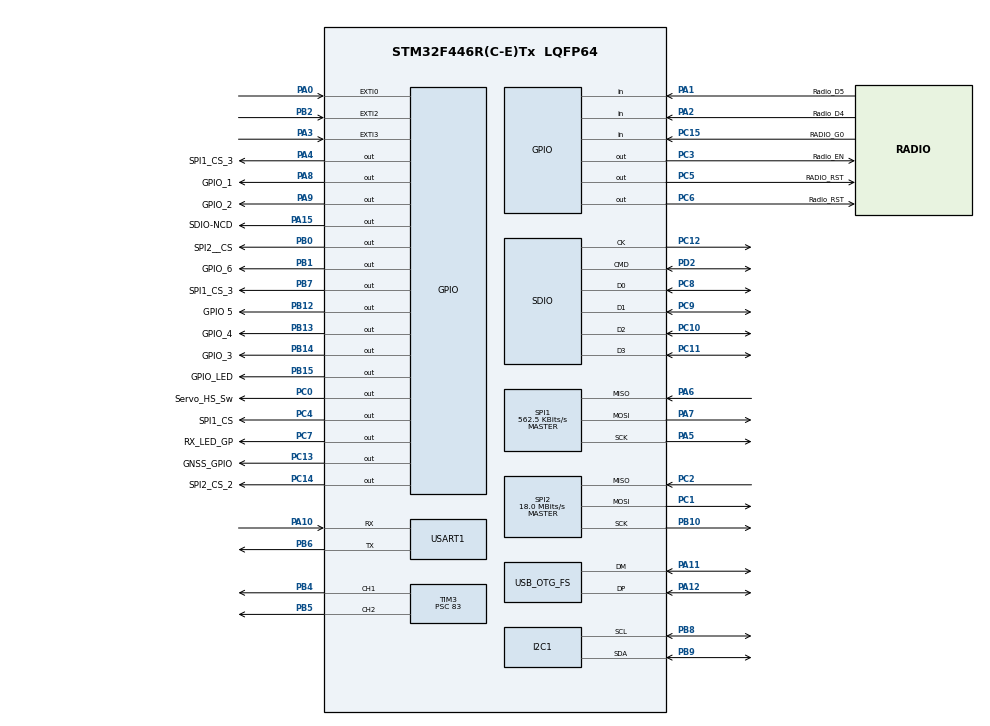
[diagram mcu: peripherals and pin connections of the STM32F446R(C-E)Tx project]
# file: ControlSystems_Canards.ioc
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Dma.Request0=SDIO_TX
Dma.Request1=SDIO_RX
Dma.SDIO_RX.1.Direction=DMA_PERIPH_TO_MEMORY
Dma.SDIO_RX.1.FIFOMode=DMA_FIFOMODE_ENABLE
Dma.SDIO_RX.1.FIFOThreshold=DMA_FIFO_THRESHOLD_FULL
Dma.SDIO_RX.1.Instance=DMA2_Stream6
Dma.SDIO_RX.1.MemBurst=DMA_MBURST_INC4
Dma.SDIO_RX.1.MemDataAlignment=DMA_MDATAALIGN_WORD
Dma.SDIO_RX.1.MemInc=DMA_MINC_ENABLE
Dma.SDIO_RX.1.Mode=DMA_PFCTRL
Dma.SDIO_RX.1.PeriphBurst=DMA_PBURST_INC4
Dma.SDIO_RX.1.PeriphDataAlignment=DMA_PDATAALIGN_WORD
Dma.SDIO_RX.1.PeriphInc=DMA_PINC_DISABLE
Dma.SDIO_RX.1.Priority=DMA_PRIORITY_HIGH
Dma.SDIO_TX.0.Direction=DMA_MEMORY_TO_PERIPH
Dma.SDIO_TX.0.FIFOMode=DMA_FIFOMODE_ENABLE
Dma.SDIO_TX.0.FIFOThreshold=DMA_FIFO_THRESHOLD_FULL
Dma.SDIO_TX.0.Instance=DMA2_Stream3
Dma.SDIO_TX.0.MemBurst=DMA_MBURST_INC4
Dma.SDIO_TX.0.MemDataAlignment=DMA_MDATAALIGN_WORD
Dma.SDIO_TX.0.MemInc=DMA_MINC_ENABLE
Dma.SDIO_TX.0.Mode=DMA_PFCTRL
Dma.SDIO_TX.0.PeriphBurst=DMA_PBURST_INC4
Dma.SDIO_TX.0.PeriphDataAlignment=DMA_PDATAALIGN_WORD
Dma.SDIO_TX.0.PeriphInc=DMA_PINC_DISABLE
Dma.SDIO_TX.0.Priority=DMA_PRIORITY_HIGH
FATFS._FS_NORTC=1
FREERTOS.Tasks01=defaultTask,24,128,StartDefaultTask,Default,NULL,Dynamic,NULL,NULL
IWDG.Prescaler=IWDG_PRESCALER_32
IWDG.Reload=1000
Mcu.Family=STM32F4
Mcu.Name=STM32F446R(C-E)Tx
Mcu.Package=LQFP64
NVIC.DMA2_Stream3_IRQn=true\:5\:0\:false\:false\:true\:true\:false\:true\:true
NVIC.DMA2_Stream6_IRQn=true\:5\:0\:false\:false\:true\:true\:false\:true\:true
NVIC.EXTI0_IRQn=true\:5\:0\:false\:false\:true\:true\:true\:true\:true
NVIC.EXTI2_IRQn=true\:5\:0\:false\:false\:true\:true\:true\:true\:true
NVIC.EXTI3_IRQn=true\:5\:0\:false\:false\:true\:true\:true\:true\:true
NVIC.OTG_FS_IRQn=true\:5\:0\:false\:false\:true\:true\:false\:true\:true
NVIC.PriorityGroup=NVIC_PRIORITYGROUP_4
NVIC.SDIO_IRQn=true\:5\:0\:false\:false\:true\:true\:true\:true\:true
NVIC.TIM6_DAC_IRQn=true\:15\:0\:false\:false\:true\:false\:false\:true\:true
NVIC.TimeBase=TIM6_DAC_IRQn
NVIC.TimeBaseIP=TIM6
PA0-WKUP.GPIO_PuPd=GPIO_PULLDOWN
PA0-WKUP.Signal=GPXTI0
PA1.GPIO_Label=Radio_D5
PA1.GPIO_PuPd=GPIO_PULLDOWN
PA1.Signal=GPIO_Input
PA10.Mode=Asynchronous
PA10.Signal=USART1_RX
PA11.Mode=Device_Only
PA11.Signal=USB_OTG_FS_DM
PA12.Mode=Device_Only
PA12.Signal=USB_OTG_FS_DP
PA13.Mode=Trace_Asynchronous_SW
PA13.Signal=SYS_JTMS-SWDIO
PA14.Mode=Trace_Asynchronous_SW
PA14.Signal=SYS_JTCK-SWCLK
PA15.GPIO_Label=SDIO-NCD
PA15.Signal=GPIO_Output
PA2.GPIO_Label=Radio_D4
PA2.GPIO_PuPd=GPIO_PULLDOWN
PA2.Signal=GPIO_Input
PA3.GPIO_PuPd=GPIO_PULLDOWN
PA3.Signal=GPXTI3
PA4.GPIO_Label=SPI1_CS_3
PA4.Signal=GPIO_Output
PA5.Mode=Full_Duplex_Master
PA5.Signal=SPI1_SCK
PA6.Mode=Full_Duplex_Master
PA6.Signal=SPI1_MISO
PA7.Mode=Full_Duplex_Master
PA7.Signal=SPI1_MOSI
PA8.GPIO_Label=GPIO_1
PA8.Signal=GPIO_Output
PA9.GPIO_Label=GPIO_2
PA9.Signal=GPIO_Output
PB0.GPIO_Label=SPI2__CS
PB0.GPIO_PuPd=GPIO_NOPULL
PB0.Signal=GPIO_Output
PB1.GPIO_Label=GPIO_6
PB1.Signal=GPIO_Output
PB10.Mode=Full_Duplex_Master
PB10.Signal=SPI2_SCK
PB12.GPIO_Label=GPIO 5
PB12.Signal=GPIO_Output
PB13.GPIO_Label=GPIO_4
PB13.Signal=GPIO_Output
PB14.GPIO_Label=GPIO_3
PB14.Signal=GPIO_Output
PB15.GPIO_Label=GPIO_LED
PB15.Signal=GPIO_Output
PB2.GPIO_PuPd=GPIO_PULLDOWN
PB2.Signal=GPXTI2
PB3.Mode=Trace_Asynchronous_SW
PB3.Signal=SYS_JTDO-SWO
PB4.Signal=S_TIM3_CH1
PB5.Signal=S_TIM3_CH2
PB6.Mode=Asynchronous
PB6.Signal=USART1_TX
PB7.GPIO_Label=SPI1_CS_3
PB7.GPIO_Speed=GPIO_SPEED_FREQ_VERY_HIGH
PB7.PinState=GPIO_PIN_SET
PB7.Signal=GPIO_Output
PB8.Mode=I2C
PB8.Signal=I2C1_SCL
PB9.Mode=I2C
PB9.Signal=I2C1_SDA
PC0.GPIO_Label=Servo_HS_Sw
PC0.Signal=GPIO_Output
PC1.Mode=Full_Duplex_Master
PC1.Signal=SPI2_MOSI
PC10.Mode=SD_4_bits_Wide_bus
PC10.Signal=SDIO_D2
PC11.Mode=SD_4_bits_Wide_bus
PC11.Signal=SDIO_D3
PC12.Mode=SD_4_bits_Wide_bus
PC12.Signal=SDIO_CK
PC13.GPIO_Label=GNSS_GPIO
PC13.Signal=GPIO_Output
PC14-OSC32_IN.GPIO_Label=SPI2_CS_2
PC14-OSC32_IN.Signal=GPIO_Output
PC15-OSC32_OUT.GPIO_Label=RADIO_G0
PC15-OSC32_OUT.GPIO_PuPd=GPIO_PULLDOWN
PC15-OSC32_OUT.Signal=GPIO_Input
PC2.Mode=Full_Duplex_Master
PC2.Signal=SPI2_MISO
PC3.GPIO_Label=Radio_EN
PC3.Signal=GPIO_Output
PC4.GPIO_Label=SPI1_CS
PC4.GPIO_PuPd=GPIO_NOPULL
PC4.GPIO_Speed=GPIO_SPEED_FREQ_VERY_HIGH
PC4.PinState=GPIO_PIN_SET
PC4.Signal=GPIO_Output
PC5.GPIO_Label=RADIO_RST
PC5.GPIO_PuPd=GPIO_PULLUP
PC5.Signal=GPIO_Output
PC6.GPIO_Label=Radio_RST
PC6.Signal=GPIO_Output
PC7.GPIO_Label=RX_LED_GP
PC7.Signal=GPIO_Output
PC8.Mode=SD_4_bits_Wide_bus
PC8.Signal=SDIO_D0
PC9.Mode=SD_4_bits_Wide_bus
PC9.Signal=SDIO_D1
PD2.Mode=SD_4_bits_Wide_bus
PD2.Signal=SDIO_CMD
PH0-OSC_IN.Mode=HSE-External-Clock-Source
PH0-OSC_IN.Signal=RCC_OSC_IN
PH1-OSC_OUT.Mode=HSE-External-Clock-Source
PH1-OSC_OUT.Signal=RCC_OSC_OUT
ProjectManager.HeapSize=0x200
ProjectManager.StackSize=0x400
ProjectManager.TargetToolchain=CMake
RCC.AHBFreq_Value=72000000
RCC.APB1CLKDivider=RCC_HCLK_DIV2
RCC.APB1Freq_Value=36000000
RCC.APB1TimFreq_Value=72000000
RCC.APB2Freq_Value=72000000
RCC.APB2TimFreq_Value=72000000
RCC.CortexFreq_Value=72000000
RCC.HCLKFreq_Value=72000000
RCC.HSE_VALUE=20000000
RCC.PLLM=10
RCC.PLLN=72
RCC.PLLQ=3
RCC.SYSCLKFreq_VALUE=72000000
RCC.SYSCLKSource=RCC_SYSCLKSOURCE_PLLCLK
RCC.USBFreq_Value=48000000
RCC.VCOOutputFreq_Value=144000000
SDIO.ClockDiv=118
SH.S_TIM3_CH1.0=TIM3_CH1,PWM Generation1 CH1
SH.S_TIM3_CH2.0=TIM3_CH2,PWM Generation2 CH2
SPI1.BaudRatePrescaler=SPI_BAUDRATEPRESCALER_128
SPI1.CLKPhase=SPI_PHASE_1EDGE
SPI1.CLKPolarity=SPI_POLARITY_LOW
SPI1.CRCCalculation=SPI_CRCCALCULATION_DISABLE
SPI1.CalculateBaudRate=562.5 KBits/s
SPI1.Direction=SPI_DIRECTION_2LINES
SPI1.Mode=SPI_MODE_MASTER
SPI1.VirtualType=VM_MASTER
SPI2.BaudRatePrescaler=SPI_BAUDRATEPRESCALER_2
SPI2.CalculateBaudRate=18.0 MBits/s
SPI2.Direction=SPI_DIRECTION_2LINES
SPI2.Mode=SPI_MODE_MASTER
SPI2.VirtualType=VM_MASTER
TIM3.Channel-PWM\ Generation1\ CH1=TIM_CHANNEL_1
TIM3.Channel-PWM\ Generation2\ CH2=TIM_CHANNEL_2
TIM3.Period=19999
TIM3.Prescaler=83
USART1.VirtualMode=VM_ASYNC
USB_DEVICE.CLASS_NAME_FS=CDC
USB_DEVICE.VirtualMode-CDC_FS=Cdc
USB_DEVICE.VirtualModeFS=Cdc_FS
USB_OTG_FS.VirtualMode=Device_Only
VP_FATFS_VS_SDIO.Mode=SDIO
VP_FREERTOS_VS_CMSIS_V2.Mode=CMSIS_V2
VP_IWDG_VS_IWDG.Mode=IWDG_Activate
VP_SYS_VS_tim6.Mode=TIM6
VP_TIM3_VS_ClockSourceINT.Mode=Internal
VP_USB_DEVICE_VS_USB_DEVICE_CDC_FS.Mode=CDC_FS
board=custom

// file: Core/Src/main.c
/* USER CODE BEGIN Header */
/**
 ******************************************************************************
 * @file           : main.c
 * @brief          : Main program body
 ******************************************************************************
 * @attention
 *
 * Copyright (c) 2026 STMicroelectronics.
 * All rights reserved.
 *
 * This software is licensed under terms that can be found in the LICENSE file
 * in the root directory of this software component.
 * If no LICENSE file comes with this software, it is provided AS-IS.
 *
 ******************************************************************************
 */
/* USER CODE END Header */
#include "main.h"
#include "cmsis_os.h"
#include "dma.h"
#include "fatfs.h"
#include "i2c.h"
#include "iwdg.h"
#include "sdio.h"
#include "spi.h"
#include "tim.h"
#include "usart.h"
#include "usb_device.h"
#include "gpio.h"

void SystemClock_Config(void);
void MX_FREERTOS_Init(void);

int main(void)
{

  /* MCU Configuration--------------------------------------------------------*/

  /* Reset of all peripherals, Initializes the Flash interface and the Systick. */

  HAL_Init();

  /* USER CODE BEGIN Init */
  // Enable FPU (Floating Point Unit)
  SCB->CPACR |= ((3UL << (10 * 2)) | (3UL << (11 * 2)));
  __DSB();
  __ISB();
  /* USER CODE END Init */

  /* Configure the system clock */
  SystemClock_Config();

  /* Initialize all configured peripherals */
  MX_GPIO_Init();
  MX_DMA_Init();
  MX_SPI1_Init();
  MX_SPI2_Init();
  MX_I2C1_Init();
  MX_TIM3_Init();
  MX_USART1_UART_Init();
  MX_SDIO_SD_Init();
  MX_FATFS_Init();
  MX_IWDG_Init();
  /* USER CODE BEGIN 2 */
  if (__HAL_RCC_GET_FLAG(RCC_FLAG_IWDGRST))
  {
    // reset the flags
    __HAL_RCC_CLEAR_RESET_FLAGS();
  }
  HAL_TIM_PWM_Start(&htim3, TIM_CHANNEL_2);
  HAL_TIM_PWM_Start(&htim3, TIM_CHANNEL_1);

  /* USER CODE END 2 */

  /* Init scheduler */
  osKernelInitialize(); /* Call init function for freertos objects (in cmsis_os2.c) */
  MX_FREERTOS_Init();
  /* Start scheduler */
  osKernelStart();

  /* We should never get here as control is now taken by the scheduler */

  /* Infinite loop */
  while (1)
  {

  }
}

void SystemClock_Config(void)
{
  RCC_OscInitTypeDef RCC_OscInitStruct = {0};
  RCC_ClkInitTypeDef RCC_ClkInitStruct = {0};

  /** Configure the main internal regulator output voltage
   */
  __HAL_RCC_PWR_CLK_ENABLE();
  __HAL_PWR_VOLTAGESCALING_CONFIG(PWR_REGULATOR_VOLTAGE_SCALE1);

  /** Initializes the RCC Oscillators according to the specified parameters
   * in the RCC_OscInitTypeDef structure.
   */
  RCC_OscInitStruct.OscillatorType = RCC_OSCILLATORTYPE_LSI | RCC_OSCILLATORTYPE_HSE;
  RCC_OscInitStruct.HSEState = RCC_HSE_BYPASS;
  RCC_OscInitStruct.LSIState = RCC_LSI_ON;
  RCC_OscInitStruct.PLL.PLLState = RCC_PLL_ON;
  RCC_OscInitStruct.PLL.PLLSource = RCC_PLLSOURCE_HSE;
  RCC_OscInitStruct.PLL.PLLM = 10;
  RCC_OscInitStruct.PLL.PLLN = 144;
  RCC_OscInitStruct.PLL.PLLP = RCC_PLLP_DIV2;
  RCC_OscInitStruct.PLL.PLLQ = 6;
  RCC_OscInitStruct.PLL.PLLR = 2;
  if (HAL_RCC_OscConfig(&RCC_OscInitStruct) != HAL_OK)
  {
    Error_Handler();
  }

  /** Initializes the CPU, AHB and APB buses clocks
   */
  RCC_ClkInitStruct.ClockType = RCC_CLOCKTYPE_HCLK | RCC_CLOCKTYPE_SYSCLK | RCC_CLOCKTYPE_PCLK1 | RCC_CLOCKTYPE_PCLK2;
  RCC_ClkInitStruct.SYSCLKSource = RCC_SYSCLKSOURCE_PLLCLK;
  RCC_ClkInitStruct.AHBCLKDivider = RCC_SYSCLK_DIV1;
  RCC_ClkInitStruct.APB1CLKDivider = RCC_HCLK_DIV4;
  RCC_ClkInitStruct.APB2CLKDivider = RCC_HCLK_DIV2;

  if (HAL_RCC_ClockConfig(&RCC_ClkInitStruct, FLASH_LATENCY_4) != HAL_OK)
  {
    Error_Handler();
  }
}

void HAL_TIM_PeriodElapsedCallback(TIM_HandleTypeDef *htim)
{
  if (htim->Instance == TIM6)
  {
    HAL_IncTick();
  }
}

void Error_Handler(void)
{
  __disable_irq();
  while (1)
  {
  }
}

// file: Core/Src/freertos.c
#include "FreeRTOS.h"
#include "Drivers/mmc5983ma.h"
#include "Drivers/lsm6dso32_app.h"
#include "StateEstimation/altitude_estimation.h"
#include "Utils/math_utils.h"
#include "Defs/states.h"
#include "cmsis_os2.h"
#include "projdefs.h"
#include "stm32f4xx_hal_def.h"
#include "task.h"
#include "main.h"
#include "cmsis_os.h"
#include "semphr.h"
#include "usart.h"
#include "spi.h"
#include "stdint.h"
#include <stdio.h>
#include <stdbool.h>
#include "iwdg.h"
#include <string.h>
#include "fatfs.h"
#include <math.h>
#include "Configs/flight_configs.h"
#include "Utils/servo.h"
#include "Drivers/rfm69.h"
#include "i2c.h"
#include "Drivers/ms5611.h"
#include "attitude_estimation_wrapper.h"
#include "queue.h"
#include <string.h>
// #include "rfm69.h"
#include "Tasks/sensor.h"
#include "Tasks/sdcard.h"
#include "Tasks/launchDet.h"
#include "Tasks/radio.h"
#include "Drivers/rfm9x.h"
#include "Tasks/gps.h"
#include "tim.h"

extern FATFS SDFatFS;
extern FIL SDFile;
extern char SDPath[4];
extern SD_HandleTypeDef hsd;
bool sdInitialized = false;

SemaphoreHandle_t xMagDataReadySemaphore;
SemaphoreHandle_t xImuAccelReadySemaphore;
SemaphoreHandle_t xImuGyroReadySemaphore;
SemaphoreHandle_t gI2c1Mutex;
SemaphoreHandle_t gSpi1Mutex;
SemaphoreHandle_t gSpi2Mutex;

osThreadId_t readSensorTaskHandle;
osThreadId_t altEstTaskHandle;
osThreadId_t oriEstTaskHandle;
osThreadId_t launchDetTaskHandle;
osThreadId_t dataStoreTaskHandle;
// osThreadId_t gpsRetrieveTaskHandle;
osThreadId_t radioTaskHandle;
osThreadId_t controlTaskHandle;
osThreadId_t heartbeatTaskHandle;
osThreadId_t gpsTaskHandle;

// QueueHandle_t radioQueueHandle;

// struct data handle init
Rocket_States_t Rocket = {.flightState = STATE_PAD};

// watchdog task flags
volatile bool readSensorTask = false;
volatile bool altEstTask = false;
volatile bool launchDetTask = false;
volatile bool dataStoreTask = false;
// volatile bool radioTask = false;
volatile bool controlTask = false;
volatile bool oriEstTask = false;
volatile bool gpsTask = false; // not in the watchdog check, like the radio

// Priorities follow the data pipeline (high -> low):
//   readSensor -> launchDet -> oriEst -> altEst -> control -> dataStore -> heartbeat
// so each stage preempts and runs as soon as its input is ready. Heartbeat is lowest
// on purpose: the IWDG only gets refreshed when every real task is idle/healthy.
const osThreadAttr_t readSensorTask_attributes = {
    .name = "readSensorTask", .stack_size = 1024 * 4, .priority = osPriorityAboveNormal7};
const osThreadAttr_t altEstTask_attributes = {
    .name = "altTask", .stack_size = 1024 * 4, .priority = osPriorityAboveNormal4};
const osThreadAttr_t oriEstTask_attributes = {
    .name = "attitudeTask", .stack_size = 1024 * 16, .priority = osPriorityAboveNormal5};
const osThreadAttr_t launchDetTask_attributes = {
    .name = "launchTask", .stack_size = 1024 * 2, .priority = osPriorityAboveNormal6};
const osThreadAttr_t dataStoreTask_attributes = {
    .name = "storeTask", .stack_size = 1024 * 4, .priority = osPriorityAboveNormal1};
const osThreadAttr_t controlTask_attributes = {
    .name = "controlCanards", .stack_size = 1024 * 4, .priority = osPriorityAboveNormal3};
const osThreadAttr_t heartbeat_attributes = {
    .name = "wdgTask", .stack_size = 256 * 4, .priority = osPriorityBelowNormal3};
const osThreadAttr_t radiotask_attributes = {
    .name = "radioTask", .stack_size = 1024 * 4, .priority = osPriorityNormal};
const osThreadAttr_t gps_attributes = {
    .name = "gpsTask", .stack_size = 1024 * 4, .priority = osPriorityNormal};

void vGpsTask(void *argument);
void vReadSensorTask(void *argument);
void vAltEstTask(void *argument);
void vOriEstTask(void *argument);
void vLaunchDetTask(void *argument);
void vDataStoreTask(void *argument);
void vControlTask(void *argument);
void vRadioTask(void *argument);
void vHeartbeatTask(void *argument);
void MX_FREERTOS_Init(void);

void MX_FREERTOS_Init(void)
{
  gI2c1Mutex = xSemaphoreCreateMutex();
  gSpi1Mutex = xSemaphoreCreateMutex();
  gSpi2Mutex = xSemaphoreCreateMutex();
  xMagDataReadySemaphore = xSemaphoreCreateBinary();
  xImuAccelReadySemaphore = xSemaphoreCreateBinary();
  xImuGyroReadySemaphore = xSemaphoreCreateBinary();

  configASSERT(gI2c1Mutex);
  configASSERT(gSpi1Mutex);
  configASSERT(gSpi2Mutex);
  configASSERT(xMagDataReadySemaphore);
  configASSERT(xImuAccelReadySemaphore);
  configASSERT(xImuGyroReadySemaphore);

  readSensorTaskHandle = osThreadNew(vReadSensorTask, NULL, &readSensorTask_attributes);
  altEstTaskHandle = osThreadNew(vAltEstTask, NULL, &altEstTask_attributes);
  oriEstTaskHandle = osThreadNew(vOriEstTask, NULL, &oriEstTask_attributes);
  launchDetTaskHandle = osThreadNew(vLaunchDetTask, NULL, &launchDetTask_attributes);
  dataStoreTaskHandle = osThreadNew(vDataStoreTask, NULL, &dataStoreTask_attributes);
  controlTaskHandle = osThreadNew(vControlTask, NULL, &controlTask_attributes);
  radioTaskHandle = osThreadNew(vRadioTask, NULL, &radiotask_attributes);
  gpsTaskHandle = osThreadNew(vGpsTask, NULL, &gps_attributes);
  heartbeatTaskHandle = osThreadNew(vHeartbeatTask, NULL, &heartbeat_attributes);
}

void vGpsTask(void *argument)
{
  static uint8_t dummy_tx[GPS_BUF_SIZE];
  memset(dummy_tx, 0xFF, sizeof(dummy_tx));
  uint8_t gpsData[GPS_BUF_SIZE];
  GNSS_Data vehicle_gps;
  memset(&vehicle_gps, 0, sizeof(GNSS_Data));
  CS_HIGH();
  vTaskDelay(pdMS_TO_TICKS(1500));
  // only used for setting up the gps
  // gpsSendCfg(cfg_revert, sizeof(cfg_revert));
  // vTaskDelay(pdMS_TO_TICKS(500));
  // gpsSendCfg(cfg_spiprot, sizeof(cfg_spiprot));
  // vTaskDelay(pdMS_TO_TICKS(500));
  for (;;)
  {
    gpsRead(gSpi2Mutex, gpsData, dummy_tx);
    process_gps_data((char *)gpsData, &vehicle_gps);
    taskENTER_CRITICAL();
    Rocket.gps.has_fix = vehicle_gps.has_fix;
    Rocket.gps.latitude = vehicle_gps.latitude;
    Rocket.gps.longitude = vehicle_gps.longitude;
    Rocket.gps.altitude_m = vehicle_gps.altitude_m;
    Rocket.gps.speed_kmh = vehicle_gps.speed_kmh;
    taskEXIT_CRITICAL();
    osDelay(1000);
    gpsTask = true;
  }
}

void vReadSensorTask(void *argument)
{
  HAL_GPIO_WritePin(GPIOB, GPIO_PIN_0, GPIO_PIN_SET);
  sensor_HardwareInit();

  for (;;)
  {
    // I2C1: Magnetometer
    sensor_ReadMagnetometer();

    // SPI2: Barometer
    sensor_ReadBarometer();

    // SPI1: IMU - accelerometer
    sensor_ReadIMUAccelerometer();

    // SPI1: IMU - gyro
    sensor_ReadIMUGyro();

    Rocket.rawData.timestamp = osKernelGetTickCount();

    sensor_GroundReference();

    HAL_GPIO_TogglePin(GPIOC, GPIO_PIN_7);
    readSensorTask = true;
    osDelay(10);
  }
}

void vAltEstTask(void *argument)
{
  // Process noise - accounts for accelerometer noise AND unmodeled dynamics
  // These values work well for rocket flights where there are aerodynamic effects
  // the simple kinematic model doesn't capture
  float processNoise[2][2] = {
      {0.01f, 0.0f}, // Position process noise (m²)
      {0.0f, 0.1f}   // Velocity process noise (m²/s²) - increased because velocity compounds errors faster
  };

  // Initial uncertainty - start with high uncertainty, filter will converge quickly
  static float systemCov[2][2] = {
      {10.0f, 0.0f}, // Initial altitude uncertainty (m²) - about ±3m standard deviation
      {0.0f, 25.0f}  // Initial velocity uncertainty (m²/s²) - about ±5 m/s standard deviation
  };

  // State transition matrix - pure kinematics, will be updated each cycle
  float stateTransition[2][2] = {
      {1.0f, 0.0f}, // Altitude carries forward
      {0.0f, 1.0f}  // Velocity carries forward
  };
  // Note: stateTransition[0][1] gets set to dt each iteration in your code

  // Barometer measurement noise - MS5611 in flight conditions
  // Using 1.0 accounts for vibration and dynamic pressure effects during flight
  const float baroAltVar = 1.0f; // Variance in m² (standard deviation ≈ 1.0m)

  static uint32_t last_tick = 0;
  float dt = 0.0f;

  float accel_in_m_s2;
  float baro_altitude;

  for (;;)
  {
    ulTaskNotifyTake(pdTRUE, portMAX_DELAY);

    uint32_t current_tick = osKernelGetTickCount();

    dt = (float)(current_tick - last_tick) / 1000.0f;
    last_tick = current_tick;

    if (dt < 0.001f)
      dt = 0.01f;
    if (dt > 0.1f)
      dt = 0.1f;

    stateTransition[0][1] = dt;

    accel_in_m_s2 = (Rocket.rawData.accel[2] - 1000.0f) * 0.00980665f * cosf(Rocket.estimate.tilt_angle * M_PI / 180.0f);
    if (fabsf(accel_in_m_s2) > 500.0f)
      accel_in_m_s2 = 0.0f;

    altPredict(dt, &Rocket.estimate.position, &Rocket.estimate.velocity,
               accel_in_m_s2, processNoise, systemCov, stateTransition);

    baro_altitude = getRelativeAltitude(Rocket.rawData.pressure);
    altUpdate(&Rocket.estimate.position, &Rocket.estimate.velocity,
              baro_altitude, systemCov, baroAltVar);

    // update rocket state estimate and gyro integration
    Rocket.estimate.timestamp = current_tick;
    Rocket.estimate.acceleration = accel_in_m_s2;

    altEstTask = true;
  }
}

void vOriEstTask(void *argument)
{
  AttitudeEstimationHandle attitudeEstimationHandle = AttitudeEstimation_create();
  float attitude[4];
  float attitudeRPY[3];
  static uint32_t last_tick = 0;
  float dt;

  for (;;)
  {
    ulTaskNotifyTake(pdTRUE, portMAX_DELAY);

    uint32_t current_tick = osKernelGetTickCount();
    dt = (float)(current_tick - last_tick) / 1000.0f;
    last_tick = current_tick;
    if (dt < 0.001f)
      dt = 0.01f;
    if (dt > 0.1f)
      dt = 0.1f;
    AttitudeEstimation_setDt(attitudeEstimationHandle, dt);

    // Accel frame fix: roll & pitch came out anti-correlated with gravity because the
    // accelerometer X/Y axes are 180 deg about Z relative to the estimator body frame.
    // Negate X and Y (NOT Z, so gravity magnitude and the altitude KF's accel[2] use stay intact).
    float accelCorr[3] = {
        -Rocket.rawData.accel[0],
        -Rocket.rawData.accel[1],
        Rocket.rawData.accel[2]};

    AttitudeEstimation_predict(attitudeEstimationHandle, Rocket.rawData.gyro, attitude);
    AttitudeEstimation_correct(attitudeEstimationHandle, accelCorr, Rocket.rawData.mag, attitude);
    AttitudeEstimation_getRPY(attitudeEstimationHandle, attitudeRPY);

    Rocket.estimate.rpy[0] = attitudeRPY[0];
    Rocket.estimate.rpy[1] = attitudeRPY[1];
    Rocket.estimate.rpy[2] = attitudeRPY[2];
    Rocket.estimate.tilt_angle = sqrtf(powf(Rocket.estimate.rpy[0], 2.0f) + powf(Rocket.estimate.rpy[1], 2.0f));

    xTaskNotifyGive(controlTaskHandle);
    oriEstTask = true;
  }
}

void vLaunchDetTask(void *argument)
{
  for (;;)
  {
    ulTaskNotifyTake(pdTRUE, portMAX_DELAY);

    checkRecorded();

    checkFlightState();

    notifyTasks();

    satisfyWDG();
  }
}

void vDataStoreTask(void *argument)
{
  int len; // must hold the full row length (~294 B); a uint8_t would wrap at 256 and truncate the SD write
  bool sdInitialized = DataStore_SDCardInit();
  // radioQueueHandle = xQueueCreate(1, CSV_BUFFER_SIZE); // item size must match csvBuffer so the full row isn't truncated

  for (;;)
  {
    ulTaskNotifyTake(pdTRUE, portMAX_DELAY);
    dataStoreTask = true; // always set flag first — SD ops below must not block WDG

    if (Rocket.flightState == STATE_PAD)
    {
      dataStoreTask = true;
      continue;
    }

    if (!sdInitialized)
    {
      continue;
    }

    DataStore_TelemetrySnapshot();
    len = DataStore_WriteToCSV();

    DataStore_WriteToSDCard(len);
  }
}

void vControlTask(void *argument)
{
  float setPoint = 0.0f;
  float rollError = 0;
  static float integral = 0;
  float derivative, output = 0;
  float pitchSetPoint = 0.0f;

  // On startup: power the servo and drive it to center, holding long enough
  // for it to physically reach the middle before the control loop begins.
  HAL_GPIO_WritePin(Servo_HS_Sw_GPIO_Port, Servo_HS_Sw_Pin, GPIO_PIN_SET);
  __HAL_TIM_SET_COMPARE(&htim3, TIM_CHANNEL_1, SERVO_CENTER_US);
  __HAL_TIM_SET_COMPARE(&htim3, TIM_CHANNEL_2, SERVO_CENTER_US);
  for (uint32_t t = 0; t < 500; t += 20)
  {
    controlTask = true; // keep the watchdog fed while the servo travels
    osDelay(20);
  }

  for (;;)
  {
    ulTaskNotifyTake(pdTRUE, portMAX_DELAY);

    if (Rocket.flightState == STATE_CANARDS_ACTIVATE)
    {
      uint32_t elapsedMillis = osKernelGetTickCount();

      if ((elapsedMillis % 10000) < 5000)
      {
        setPoint = 0.0f;
      }
      else
      {
        setPoint = 90.0f;
      }

      // Roll = spin about the longitudinal (Z/nose) axis = estimator yaw (rpy[2]).
      rollError = setPoint - Rocket.estimate.rpy[2];
      Rocket.control.rollError = rollError;
      Rocket.control.setPoint = setPoint;
      Rocket.control.pitchError = pitchSetPoint - Rocket.estimate.rpy[1];

      if (fabsf(Rocket.control.pitchError) > 30)
      {
        // Off-nominal pitch: cut servo power and skip actuation.
        HAL_GPIO_WritePin(Servo_HS_Sw_GPIO_Port, Servo_HS_Sw_Pin, GPIO_PIN_RESET);
        controlTask = true;
        continue;
      }

      // Canards active and pitch in range: power the servo.
      HAL_GPIO_WritePin(Servo_HS_Sw_GPIO_Port, Servo_HS_Sw_Pin, GPIO_PIN_SET);

      if (fabsf(output) < 20.0f)
      {
        integral += rollError * 0.01f;
      }

      derivative = Rocket.rawData.gyro[2]; // spin rate about the Z/nose axis
      output = (Kp * rollError) + (Ki * integral) - (Kd * derivative);

      Rocket.control.pwmAngle = moveServo(output, Rocket.estimate.velocity, Rocket.rawData.pressure);
    }
    else
    {
      // Not in the canards phase: keep the servo unpowered.
      HAL_GPIO_WritePin(Servo_HS_Sw_GPIO_Port, Servo_HS_Sw_Pin, GPIO_PIN_RESET);
      setPoint = 0.0f;
      integral = 0;
      output = 0;
    }

    controlTask = true;
  }
}

// Not part of the watchdog check, a radio fault must never reset the flight computer
void vRadioTask(void *argument)
{
  static char packet[RFM9X_MAX_PAYLOAD + 1];
  bool radioReady = false;
  uint32_t nextWake = osKernelGetTickCount();

  for (;;)
  {
    nextWake += RADIO_PERIOD_MS;

    if (!radioReady)
    {
      radioReady = (rfm9xInit() == HAL_OK);
    }

    if (radioReady)
    {
      int len = Radio_BuildPacket(packet, sizeof(packet));

      if (len > 0 && rfm9xTransmit((const uint8_t *)packet, (uint8_t)len) != HAL_OK)
      {
        radioReady = false;
      }
    }

    osDelayUntil(nextWake);
  }
}

void vHeartbeatTask(void *argument)
{
  for (;;)
  {
    HAL_GPIO_TogglePin(GPIOC, GPIO_PIN_13);

    if (readSensorTask && altEstTask && launchDetTask && dataStoreTask && controlTask && oriEstTask)
    {
      HAL_IWDG_Refresh(&hiwdg);
      HAL_GPIO_TogglePin(GPIOB, GPIO_PIN_15);
      readSensorTask = false;
      altEstTask = false;
      launchDetTask = false;
      dataStoreTask = false;
      controlTask = false;
      oriEstTask = false;
    }
    osDelay(pdMS_TO_TICKS(100));
  }
}

void HAL_GPIO_EXTI_Callback(uint16_t GPIO_Pin)
{
  BaseType_t xHigherPriorityTaskWoken = pdFALSE;

  if (GPIO_Pin == GPIO_PIN_3)
  {
    xSemaphoreGiveFromISR(xMagDataReadySemaphore, &xHigherPriorityTaskWoken);
  }
  else if (GPIO_Pin == GPIO_PIN_0)
  {
    xSemaphoreGiveFromISR(xImuAccelReadySemaphore, &xHigherPriorityTaskWoken);
  }
  else if (GPIO_Pin == GPIO_PIN_2)
  {
    xSemaphoreGiveFromISR(xImuGyroReadySemaphore, &xHigherPriorityTaskWoken);
  }

  portYIELD_FROM_ISR(xHigherPriorityTaskWoken);
}
